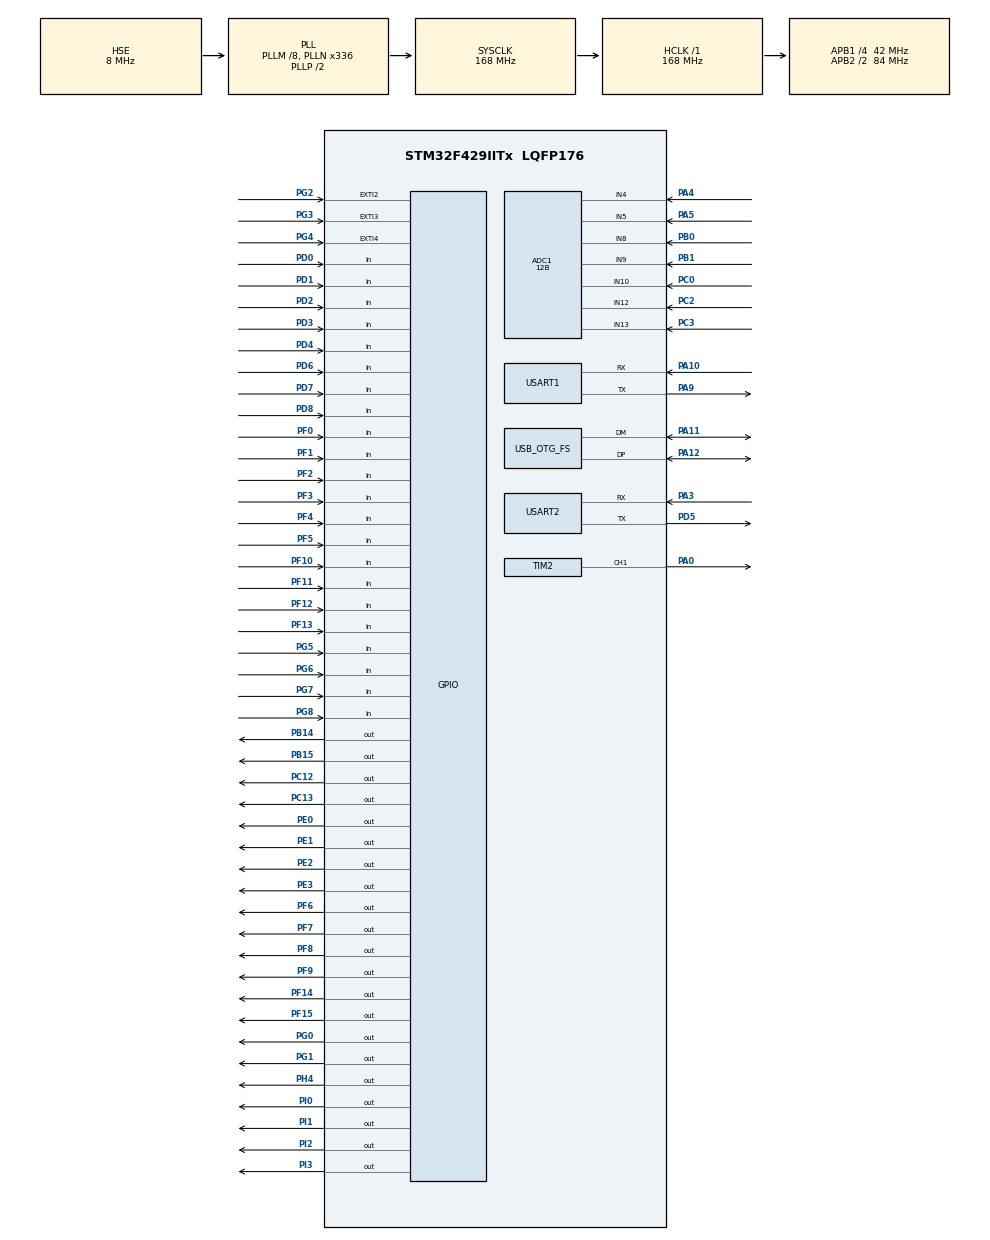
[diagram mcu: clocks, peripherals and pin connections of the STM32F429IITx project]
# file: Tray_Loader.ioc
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ADC1.Channel-0\#ChannelRegularConversion=ADC_CHANNEL_5
ADC1.Channel-1\#ChannelRegularConversion=ADC_CHANNEL_4
ADC1.ClockPrescaler=ADC_CLOCK_SYNC_PCLK_DIV4
ADC1.ContinuousConvMode=DISABLE
ADC1.DMAContinuousRequests=DISABLE
ADC1.DataAlign=ADC_DATAALIGN_RIGHT
ADC1.DiscontinuousConvMode=DISABLE
ADC1.EOCSelection=ADC_EOC_SINGLE_CONV
ADC1.EnableAnalogWatchDog=false
ADC1.ExternalTrigConv=ADC_SOFTWARE_START
ADC1.ExternalTrigConvEdge=ADC_EXTERNALTRIGCONVEDGE_NONE
ADC1.InjNumberOfConversion=0
ADC1.NbrOfConversion=2
ADC1.NbrOfConversionFlag=1
ADC1.Rank-0\#ChannelRegularConversion=1
ADC1.Rank-1\#ChannelRegularConversion=2
ADC1.Resolution=ADC_RESOLUTION_12B
ADC1.SamplingTime-0\#ChannelRegularConversion=ADC_SAMPLETIME_3CYCLES
ADC1.SamplingTime-1\#ChannelRegularConversion=ADC_SAMPLETIME_3CYCLES
ADC1.ScanConvMode=ENABLE
ADC1.master=1
Dma.Request0=USART1_RX
Dma.USART1_RX.0.Direction=DMA_PERIPH_TO_MEMORY
Dma.USART1_RX.0.FIFOMode=DMA_FIFOMODE_DISABLE
Dma.USART1_RX.0.Instance=DMA2_Stream2
Dma.USART1_RX.0.MemDataAlignment=DMA_MDATAALIGN_BYTE
Dma.USART1_RX.0.MemInc=DMA_MINC_ENABLE
Dma.USART1_RX.0.Mode=DMA_NORMAL
Dma.USART1_RX.0.PeriphDataAlignment=DMA_PDATAALIGN_BYTE
Dma.USART1_RX.0.PeriphInc=DMA_PINC_DISABLE
Dma.USART1_RX.0.Priority=DMA_PRIORITY_LOW
Mcu.Family=STM32F4
Mcu.Name=STM32F429IITx
Mcu.Package=LQFP176
NVIC.DMA2_Stream2_IRQn=true\:0\:0\:false\:false\:true\:false
NVIC.EXTI2_IRQn=true\:1\:0\:true\:false\:true\:true
NVIC.EXTI3_IRQn=true\:3\:0\:true\:false\:true\:true
NVIC.EXTI4_IRQn=true\:4\:0\:true\:false\:true\:true
NVIC.OTG_FS_IRQn=true\:0\:0\:false\:false\:true\:false
NVIC.PriorityGroup=NVIC_PRIORITYGROUP_4
NVIC.TIM2_IRQn=true\:1\:0\:true\:false\:true\:true
PA0/WKUP.Signal=S_TIM2_CH1_ETR
PA10.Mode=Asynchronous
PA10.Signal=USART1_RX
PA11.Mode=Host_Only
PA11.Signal=USB_OTG_FS_DM
PA12.Mode=Host_Only
PA12.Signal=USB_OTG_FS_DP
PA3.Mode=Asynchronous
PA3.Signal=USART2_RX
PA4.Signal=ADCx_IN4
PA5.Signal=ADCx_IN5
PA9.Mode=Asynchronous
PA9.Signal=USART1_TX
PB0.Signal=ADCx_IN8
PB1.Signal=ADCx_IN9
PB14.Signal=GPIO_Output
PB15.Signal=GPIO_Output
PC0.Signal=ADCx_IN10
PC12.Signal=GPIO_Output
PC13.Signal=GPIO_Output
PC14/OSC32_IN.Mode=LSE-External-Oscillator
PC14/OSC32_IN.Signal=RCC_OSC32_IN
PC15/OSC32_OUT.Mode=LSE-External-Oscillator
PC15/OSC32_OUT.Signal=RCC_OSC32_OUT
PC2.Signal=ADCx_IN12
PC3.Signal=ADCx_IN13
PD0.Signal=GPIO_Input
PD1.Signal=GPIO_Input
PD2.Signal=GPIO_Input
PD3.Signal=GPIO_Input
PD4.Signal=GPIO_Input
PD5.Mode=Asynchronous
PD5.Signal=USART2_TX
PD6.Signal=GPIO_Input
PD7.Signal=GPIO_Input
PD8.Signal=GPIO_Input
PE0.Signal=GPIO_Output
PE1.Signal=GPIO_Output
PE2.Signal=GPIO_Output
PE3.Signal=GPIO_Output
PF0.Signal=GPIO_Input
PF1.Signal=GPIO_Input
PF10.Signal=GPIO_Input
PF11.Signal=GPIO_Input
PF12.Signal=GPIO_Input
PF13.Signal=GPIO_Input
PF14.Signal=GPIO_Output
PF15.Signal=GPIO_Output
PF2.Signal=GPIO_Input
PF3.Signal=GPIO_Input
PF4.Signal=GPIO_Input
PF5.Signal=GPIO_Input
PF6.Signal=GPIO_Output
PF7.Signal=GPIO_Output
PF8.Signal=GPIO_Output
PF9.Signal=GPIO_Output
PG0.Signal=GPIO_Output
PG1.Signal=GPIO_Output
PG2.GPIO_ModeDefaultEXTI=GPIO_MODE_IT_FALLING
PG2.Signal=GPXTI2
PG3.GPIO_ModeDefaultEXTI=GPIO_MODE_IT_FALLING
PG3.Signal=GPXTI3
PG4.GPIO_ModeDefaultEXTI=GPIO_MODE_IT_FALLING
PG4.Signal=GPXTI4
PG5.Signal=GPIO_Input
PG6.Signal=GPIO_Input
PG7.Signal=GPIO_Input
PG8.Signal=GPIO_Input
PH0/OSC_IN.Mode=HSE-External-Oscillator
PH0/OSC_IN.Signal=RCC_OSC_IN
PH1/OSC_OUT.Mode=HSE-External-Oscillator
PH1/OSC_OUT.Signal=RCC_OSC_OUT
PH4.Signal=GPIO_Output
PI0.Signal=GPIO_Output
PI1.Signal=GPIO_Output
PI2.Signal=GPIO_Output
PI3.Signal=GPIO_Output
ProjectManager.HeapSize=0x4000
ProjectManager.StackSize=0x4000
ProjectManager.TargetToolchain=MDK-ARM V5
RCC.48MHZClocksFreq_Value=48000000
RCC.AHBFreq_Value=168000000
RCC.APB1CLKDivider=RCC_HCLK_DIV4
RCC.APB1Freq_Value=42000000
RCC.APB1TimFreq_Value=84000000
RCC.APB2CLKDivider=RCC_HCLK_DIV2
RCC.APB2Freq_Value=84000000
RCC.APB2TimFreq_Value=168000000
RCC.CortexFreq_Value=168000000
RCC.HCLKFreq_Value=168000000
RCC.HSE_VALUE=8000000
RCC.HSI_VALUE=16000000
RCC.PLLM=8
RCC.PLLN=336
RCC.PLLQ=7
RCC.RCC_RTC_Clock_Source=RCC_RTCCLKSOURCE_LSE
RCC.RCC_RTC_Clock_SourceVirtual=RCC_RTCCLKSOURCE_LSE
RCC.SYSCLKFreq_VALUE=168000000
RCC.SYSCLKSource=RCC_SYSCLKSOURCE_PLLCLK
RCC.VCOOutputFreq_Value=336000000
SH.ADCx_IN10.0=ADC1_IN10,IN10
SH.ADCx_IN12.0=ADC1_IN12,IN12
SH.ADCx_IN13.0=ADC1_IN13,IN13
SH.ADCx_IN4.0=ADC1_IN4,IN4
SH.ADCx_IN5.0=ADC1_IN5,IN5
SH.ADCx_IN8.0=ADC1_IN8,IN8
SH.ADCx_IN9.0=ADC1_IN9,IN9
SH.S_TIM2_CH1_ETR.0=TIM2_CH1,PWM Generation1 CH1
TIM1.Period=65535-1
TIM1.Prescaler=168-1
TIM2.Channel-PWM\ Generation1\ CH1=TIM_CHANNEL_1
TIM2.Period=1000-1
TIM2.Prescaler=8400-1
USART1.VirtualMode=VM_ASYNC
USART2.VirtualMode=VM_ASYNC
USB_HOST.USBH_HandleTypeDef-MSC_FS=hUsbHostFS
USB_HOST.VirtualModeFS=Msc
USB_OTG_FS.VirtualMode=Host_Only
USB_OTG_FS.phy_itface=HCD_PHY_EMBEDDED
VP_CRC_VS_CRC.Mode=CRC_Activate
VP_FATFS_VS_USB.Mode=USB
VP_RTC_VS_RTC_Activate.Mode=RTC_Enabled
VP_TIM1_VS_ClockSourceINT.Mode=Internal
VP_TIM2_VS_ClockSourceINT.Mode=Internal
VP_USB_HOST_VS_USB_HOST_MSC_FS.Mode=MSC_FS
board=custom

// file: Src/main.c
/**
  ******************************************************************************
  * @file           : main.c
  * @brief          : Main program body
  ******************************************************************************
  * This notice applies to any and all portions of this file
  * that are not between comment pairs USER CODE BEGIN and
  * USER CODE END. Other portions of this file, whether
  * inserted by the user or by software development tools
  * are owned by their respective copyright owners.
  *
  * Copyright (c) 2021 STMicroelectronics International N.V.
  * All rights reserved.
  *
  * Redistribution and use in source and binary forms, with or without
  * modification, are permitted, provided that the following conditions are met:
  *
  * 1. Redistribution of source code must retain the above copyright notice,
  *    this list of conditions and the following disclaimer.
  * 2. Redistributions in binary form must reproduce the above copyright notice,
  *    this list of conditions and the following disclaimer in the documentation
  *    and/or other materials provided with the distribution.
  * 3. Neither the name of STMicroelectronics nor the names of other
  *    contributors to this software may be used to endorse or promote products
  *    derived from this software without specific written permission.
  * 4. This software, including modifications and/or derivative works of this
  *    software, must execute solely and exclusively on microcontroller or
  *    microprocessor devices manufactured by or for STMicroelectronics.
  * 5. Redistribution and use of this software other than as permitted under
  *    this license is void and will automatically terminate your rights under
  *    this license.
  *
  * THIS SOFTWARE IS PROVIDED BY STMICROELECTRONICS AND CONTRIBUTORS "AS IS"
  * AND ANY EXPRESS, IMPLIED OR STATUTORY WARRANTIES, INCLUDING, BUT NOT
  * LIMITED TO, THE IMPLIED WARRANTIES OF MERCHANTABILITY, FITNESS FOR A
  * PARTICULAR PURPOSE AND NON-INFRINGEMENT OF THIRD PARTY INTELLECTUAL PROPERTY
  * RIGHTS ARE DISCLAIMED TO THE FULLEST EXTENT PERMITTED BY LAW. IN NO EVENT
  * SHALL STMICROELECTRONICS OR CONTRIBUTORS BE LIABLE FOR ANY DIRECT, INDIRECT,
  * INCIDENTAL, SPECIAL, EXEMPLARY, OR CONSEQUENTIAL DAMAGES (INCLUDING, BUT NOT
  * LIMITED TO, PROCUREMENT OF SUBSTITUTE GOODS OR SERVICES; LOSS OF USE, DATA,
  * OR PROFITS; OR BUSINESS INTERRUPTION) HOWEVER CAUSED AND ON ANY THEORY OF
  * LIABILITY, WHETHER IN CONTRACT, STRICT LIABILITY, OR TORT (INCLUDING
  * NEGLIGENCE OR OTHERWISE) ARISING IN ANY WAY OUT OF THE USE OF THIS SOFTWARE,
  * EVEN IF ADVISED OF THE POSSIBILITY OF SUCH DAMAGE.
  *
  ******************************************************************************
  */
#include "main.h"
#include "stm32f4xx_hal.h"
#include "fatfs.h"
#include "usb_host.h"
#include "Task_Main.h"

ADC_HandleTypeDef hadc1;

CRC_HandleTypeDef hcrc;

RTC_HandleTypeDef hrtc;

TIM_HandleTypeDef htim1;
TIM_HandleTypeDef htim2;

UART_HandleTypeDef huart1;
UART_HandleTypeDef huart2;
DMA_HandleTypeDef hdma_usart1_rx;

extern uint8_t rxBuffer[MAX_SIZE];

void SystemClock_Config(void);
static void MX_GPIO_Init(void);
static void MX_DMA_Init(void);
static void MX_ADC1_Init(void);
static void MX_CRC_Init(void);
static void MX_RTC_Init(void);
static void MX_TIM2_Init(void);
static void MX_USART1_UART_Init(void);
static void MX_USART2_UART_Init(void);
static void MX_TIM1_Init(void);
void MX_USB_HOST_Process(void);

void HAL_TIM_MspPostInit(TIM_HandleTypeDef *htim);

int main(void)
{
    HAL_Init();

    SystemClock_Config();

    MX_GPIO_Init();
    MX_DMA_Init();
    MX_ADC1_Init();
    MX_CRC_Init();
    MX_RTC_Init();
    MX_TIM2_Init();
    MX_USART1_UART_Init();
    MX_USART2_UART_Init();
    MX_FATFS_Init();
    MX_USB_HOST_Init();
    MX_TIM1_Init();

    HAL_TIM_Base_Start(&htim1);
    __HAL_TIM_ENABLE_IT(&htim2, TIM_IT_UPDATE);

    HAL_UART_Receive_DMA (&huart1, rxBuffer, RX_LEN);
    while (1)
    {
        Task_Main();
    }
}

void SystemClock_Config(void)
{

  RCC_OscInitTypeDef RCC_OscInitStruct;
  RCC_ClkInitTypeDef RCC_ClkInitStruct;
  RCC_PeriphCLKInitTypeDef PeriphClkInitStruct;

    /**Configure the main internal regulator output voltage
    */
  __HAL_RCC_PWR_CLK_ENABLE();

  __HAL_PWR_VOLTAGESCALING_CONFIG(PWR_REGULATOR_VOLTAGE_SCALE1);

    /**Initializes the CPU, AHB and APB busses clocks
    */
  RCC_OscInitStruct.OscillatorType = RCC_OSCILLATORTYPE_HSE|RCC_OSCILLATORTYPE_LSE;
  RCC_OscInitStruct.HSEState = RCC_HSE_ON;
  RCC_OscInitStruct.LSEState = RCC_LSE_ON;
  RCC_OscInitStruct.PLL.PLLState = RCC_PLL_ON;
  RCC_OscInitStruct.PLL.PLLSource = RCC_PLLSOURCE_HSE;
  RCC_OscInitStruct.PLL.PLLM = 8;
  RCC_OscInitStruct.PLL.PLLN = 336;
  RCC_OscInitStruct.PLL.PLLP = RCC_PLLP_DIV2;
  RCC_OscInitStruct.PLL.PLLQ = 7;
  if (HAL_RCC_OscConfig(&RCC_OscInitStruct) != HAL_OK)
  {
    _Error_Handler(__FILE__, __LINE__);
  }

    /**Initializes the CPU, AHB and APB busses clocks
    */
  RCC_ClkInitStruct.ClockType = RCC_CLOCKTYPE_HCLK|RCC_CLOCKTYPE_SYSCLK
                              |RCC_CLOCKTYPE_PCLK1|RCC_CLOCKTYPE_PCLK2;
  RCC_ClkInitStruct.SYSCLKSource = RCC_SYSCLKSOURCE_PLLCLK;
  RCC_ClkInitStruct.AHBCLKDivider = RCC_SYSCLK_DIV1;
  RCC_ClkInitStruct.APB1CLKDivider = RCC_HCLK_DIV4;
  RCC_ClkInitStruct.APB2CLKDivider = RCC_HCLK_DIV2;

  if (HAL_RCC_ClockConfig(&RCC_ClkInitStruct, FLASH_LATENCY_5) != HAL_OK)
  {
    _Error_Handler(__FILE__, __LINE__);
  }

  PeriphClkInitStruct.PeriphClockSelection = RCC_PERIPHCLK_RTC;
  PeriphClkInitStruct.RTCClockSelection = RCC_RTCCLKSOURCE_LSE;
  if (HAL_RCCEx_PeriphCLKConfig(&PeriphClkInitStruct) != HAL_OK)
  {
    _Error_Handler(__FILE__, __LINE__);
  }

    /**Configure the Systick interrupt time
    */
  HAL_SYSTICK_Config(HAL_RCC_GetHCLKFreq()/1000);

    /**Configure the Systick
    */
  HAL_SYSTICK_CLKSourceConfig(SYSTICK_CLKSOURCE_HCLK);

  /* SysTick_IRQn interrupt configuration */
  HAL_NVIC_SetPriority(SysTick_IRQn, 0, 0);
}

/* ADC1 init function */
static void MX_ADC1_Init(void)
{

  ADC_ChannelConfTypeDef sConfig;

    /**Configure the global features of the ADC (Clock, Resolution, Data Alignment and number of conversion)
    */
  hadc1.Instance = ADC1;
  hadc1.Init.ClockPrescaler = ADC_CLOCK_SYNC_PCLK_DIV4;
  hadc1.Init.Resolution = ADC_RESOLUTION_12B;
  hadc1.Init.ScanConvMode = ENABLE;
  hadc1.Init.ContinuousConvMode = DISABLE;
  hadc1.Init.DiscontinuousConvMode = DISABLE;
  hadc1.Init.ExternalTrigConvEdge = ADC_EXTERNALTRIGCONVEDGE_NONE;
  hadc1.Init.ExternalTrigConv = ADC_SOFTWARE_START;
  hadc1.Init.DataAlign = ADC_DATAALIGN_RIGHT;
  hadc1.Init.NbrOfConversion = 1;
  hadc1.Init.DMAContinuousRequests = DISABLE;
  hadc1.Init.EOCSelection = ADC_EOC_SINGLE_CONV;
  if (HAL_ADC_Init(&hadc1) != HAL_OK)
  {
    _Error_Handler(__FILE__, __LINE__);
  }

  /*
    //Configure for the selected ADC regular channel its corresponding rank in the sequencer and its sample time.
  sConfig.Channel = ADC_CHANNEL_5;
  sConfig.Rank = 1;
  sConfig.SamplingTime = ADC_SAMPLETIME_3CYCLES;
  if (HAL_ADC_ConfigChannel(&hadc1, &sConfig) != HAL_OK)
  {
    _Error_Handler(__FILE__, __LINE__);
  }
  */

    //Configure for the selected ADC regular channel its corresponding rank in the sequencer and its sample time.
  sConfig.Channel = ADC_CHANNEL_5;
  sConfig.Rank = 1;
  if (HAL_ADC_ConfigChannel(&hadc1, &sConfig) != HAL_OK)
  {
    _Error_Handler(__FILE__, __LINE__);
  }
}

/* CRC init function */
static void MX_CRC_Init(void)
{

  hcrc.Instance = CRC;
  if (HAL_CRC_Init(&hcrc) != HAL_OK)
  {
    _Error_Handler(__FILE__, __LINE__);
  }

}

/* RTC init function */
static void MX_RTC_Init(void)
{

    /**Initialize RTC Only
    */
  hrtc.Instance = RTC;
  hrtc.Init.HourFormat = RTC_HOURFORMAT_24;
  hrtc.Init.AsynchPrediv = 127;
  hrtc.Init.SynchPrediv = 255;
  hrtc.Init.OutPut = RTC_OUTPUT_DISABLE;
  hrtc.Init.OutPutPolarity = RTC_OUTPUT_POLARITY_HIGH;
  hrtc.Init.OutPutType = RTC_OUTPUT_TYPE_OPENDRAIN;
  if (HAL_RTC_Init(&hrtc) != HAL_OK)
  {
    _Error_Handler(__FILE__, __LINE__);
  }

}

/* TIM1 init function */
static void MX_TIM1_Init(void)
{

  TIM_ClockConfigTypeDef sClockSourceConfig;
  TIM_MasterConfigTypeDef sMasterConfig;

  htim1.Instance = TIM1;
  htim1.Init.Prescaler = 168-1;
  htim1.Init.CounterMode = TIM_COUNTERMODE_UP;
  htim1.Init.Period = 65535-1;
  htim1.Init.ClockDivision = TIM_CLOCKDIVISION_DIV1;
  htim1.Init.RepetitionCounter = 0;
  if (HAL_TIM_Base_Init(&htim1) != HAL_OK)
  {
    _Error_Handler(__FILE__, __LINE__);
  }

  sClockSourceConfig.ClockSource = TIM_CLOCKSOURCE_INTERNAL;
  if (HAL_TIM_ConfigClockSource(&htim1, &sClockSourceConfig) != HAL_OK)
  {
    _Error_Handler(__FILE__, __LINE__);
  }

  sMasterConfig.MasterOutputTrigger = TIM_TRGO_RESET;
  sMasterConfig.MasterSlaveMode = TIM_MASTERSLAVEMODE_DISABLE;
  if (HAL_TIMEx_MasterConfigSynchronization(&htim1, &sMasterConfig) != HAL_OK)
  {
    _Error_Handler(__FILE__, __LINE__);
  }

}

/* TIM2 init function */
static void MX_TIM2_Init(void)
{

    //TIME UPDATE FREQUENCY = TIM_CLK/(TIM_PSC+1)/(PERIOD + 1)
    // PWM FREQUENCY = 20 KHz
  TIM_ClockConfigTypeDef sClockSourceConfig;
  TIM_MasterConfigTypeDef sMasterConfig;
  TIM_OC_InitTypeDef sConfigOC;

  htim2.Instance = TIM2;
  htim2.Init.Prescaler = 42-1;     //8400-1;
  htim2.Init.CounterMode = TIM_COUNTERMODE_UP;
  htim2.Init.Period = 100-1;        // 1000-1
  htim2.Init.ClockDivision = TIM_CLOCKDIVISION_DIV1;
  if (HAL_TIM_Base_Init(&htim2) != HAL_OK)
  {
    _Error_Handler(__FILE__, __LINE__);
  }

  sClockSourceConfig.ClockSource = TIM_CLOCKSOURCE_INTERNAL;
  if (HAL_TIM_ConfigClockSource(&htim2, &sClockSourceConfig) != HAL_OK)
  {
    _Error_Handler(__FILE__, __LINE__);
  }

  if (HAL_TIM_PWM_Init(&htim2) != HAL_OK)
  {
    _Error_Handler(__FILE__, __LINE__);
  }

  sMasterConfig.MasterOutputTrigger = TIM_TRGO_RESET;
  sMasterConfig.MasterSlaveMode = TIM_MASTERSLAVEMODE_DISABLE;
  if (HAL_TIMEx_MasterConfigSynchronization(&htim2, &sMasterConfig) != HAL_OK)
  {
    _Error_Handler(__FILE__, __LINE__);
  }

  sConfigOC.OCMode = TIM_OCMODE_PWM1;
  sConfigOC.Pulse = 25;
  sConfigOC.OCPolarity = TIM_OCPOLARITY_HIGH;
  sConfigOC.OCFastMode = TIM_OCFAST_DISABLE;
  if (HAL_TIM_PWM_ConfigChannel(&htim2, &sConfigOC, TIM_CHANNEL_1) != HAL_OK)
  {
    _Error_Handler(__FILE__, __LINE__);
  }

  HAL_TIM_MspPostInit(&htim2);

}

/* USART1 init function */
static void MX_USART1_UART_Init(void)
{

  huart1.Instance = USART1;
  huart1.Init.BaudRate = 115200;
  huart1.Init.WordLength = UART_WORDLENGTH_8B;
  huart1.Init.StopBits = UART_STOPBITS_1;
  huart1.Init.Parity = UART_PARITY_NONE;
  huart1.Init.Mode = UART_MODE_TX_RX;
  huart1.Init.HwFlowCtl = UART_HWCONTROL_NONE;
  huart1.Init.OverSampling = UART_OVERSAMPLING_16;
  if (HAL_UART_Init(&huart1) != HAL_OK)
  {
    _Error_Handler(__FILE__, __LINE__);
  }

}

/* USART2 init function */
static void MX_USART2_UART_Init(void)
{

  huart2.Instance = USART2;
  huart2.Init.BaudRate = 115200;
  huart2.Init.WordLength = UART_WORDLENGTH_8B;
  huart2.Init.StopBits = UART_STOPBITS_1;
  huart2.Init.Parity = UART_PARITY_NONE;
  huart2.Init.Mode = UART_MODE_TX_RX;
  huart2.Init.HwFlowCtl = UART_HWCONTROL_NONE;
  huart2.Init.OverSampling = UART_OVERSAMPLING_16;
  if (HAL_UART_Init(&huart2) != HAL_OK)
  {
    _Error_Handler(__FILE__, __LINE__);
  }

}

static void MX_DMA_Init(void)
{
  /* DMA controller clock enable */
  __HAL_RCC_DMA2_CLK_ENABLE();

  /* DMA interrupt init */
  /* DMA2_Stream2_IRQn interrupt configuration */
  HAL_NVIC_SetPriority(DMA2_Stream2_IRQn, 0, 0);
  HAL_NVIC_EnableIRQ(DMA2_Stream2_IRQn);

}

/** Configure pins as
        * Analog
        * Input
        * Output
        * EVENT_OUT
        * EXTI
*/
static void MX_GPIO_Init(void)
{

  GPIO_InitTypeDef GPIO_InitStruct;

  /* GPIO Ports Clock Enable */
  __HAL_RCC_GPIOE_CLK_ENABLE();
  __HAL_RCC_GPIOC_CLK_ENABLE();
  __HAL_RCC_GPIOF_CLK_ENABLE();
  __HAL_RCC_GPIOH_CLK_ENABLE();
  __HAL_RCC_GPIOA_CLK_ENABLE();
  __HAL_RCC_GPIOB_CLK_ENABLE();
  __HAL_RCC_GPIOG_CLK_ENABLE();
  __HAL_RCC_GPIOD_CLK_ENABLE();
  __HAL_RCC_GPIOI_CLK_ENABLE();

  /*Configure GPIO pin Output Level */
  HAL_GPIO_WritePin(GPIOE, GPIO_PIN_2|GPIO_PIN_3|GPIO_PIN_0|GPIO_PIN_1, GPIO_PIN_RESET);

  /*Configure GPIO pin Output Level */
  HAL_GPIO_WritePin(GPIOC, GPIO_PIN_13|GPIO_PIN_12, GPIO_PIN_RESET);

  /*Configure GPIO pin Output Level */
  HAL_GPIO_WritePin(GPIOF, GPIO_PIN_6|GPIO_PIN_7|GPIO_PIN_8|GPIO_PIN_9
                          |GPIO_PIN_14|GPIO_PIN_15, GPIO_PIN_RESET);

  /*Configure GPIO pin Output Level */
  HAL_GPIO_WritePin(GPIOH, GPIO_PIN_4, GPIO_PIN_RESET);

  /*Configure GPIO pin Output Level */
  HAL_GPIO_WritePin(GPIOG, GPIO_PIN_0|GPIO_PIN_1, GPIO_PIN_RESET);

  /*Configure GPIO pin Output Level */
  HAL_GPIO_WritePin(GPIOB, GPIO_PIN_14|GPIO_PIN_15, GPIO_PIN_RESET);

  /*Configure GPIO pin Output Level */
  HAL_GPIO_WritePin(GPIOI, GPIO_PIN_0|GPIO_PIN_1|GPIO_PIN_2|GPIO_PIN_3, GPIO_PIN_RESET);

  /*Configure GPIO pins : PE2 PE3 PE0 PE1 */
  GPIO_InitStruct.Pin = GPIO_PIN_2|GPIO_PIN_3|GPIO_PIN_0|GPIO_PIN_1;
  GPIO_InitStruct.Mode = GPIO_MODE_OUTPUT_PP;
  GPIO_InitStruct.Pull = GPIO_NOPULL;
  GPIO_InitStruct.Speed = GPIO_SPEED_FREQ_LOW;
  HAL_GPIO_Init(GPIOE, &GPIO_InitStruct);

  /*Configure GPIO pins : PC13 PC12 */
  GPIO_InitStruct.Pin = GPIO_PIN_13|GPIO_PIN_12;
  GPIO_InitStruct.Mode = GPIO_MODE_OUTPUT_PP;
  GPIO_InitStruct.Pull = GPIO_NOPULL;
  GPIO_InitStruct.Speed = GPIO_SPEED_FREQ_LOW;
  HAL_GPIO_Init(GPIOC, &GPIO_InitStruct);

  /*Configure GPIO pins : PF0 PF1 PF2 PF3
                           PF4 PF5 PF10 PF11
                           PF12 PF13 */
  GPIO_InitStruct.Pin = GPIO_PIN_0|GPIO_PIN_1|GPIO_PIN_2|GPIO_PIN_3
                          |GPIO_PIN_4|GPIO_PIN_5|GPIO_PIN_10|GPIO_PIN_11
                          |GPIO_PIN_12|GPIO_PIN_13;
  GPIO_InitStruct.Mode = GPIO_MODE_INPUT;
  GPIO_InitStruct.Pull = GPIO_NOPULL;
  HAL_GPIO_Init(GPIOF, &GPIO_InitStruct);

  /*Configure GPIO pins : PF6 PF7 PF8 PF9
                           PF14 PF15 */
  GPIO_InitStruct.Pin = GPIO_PIN_6|GPIO_PIN_7|GPIO_PIN_8|GPIO_PIN_9
                          |GPIO_PIN_14|GPIO_PIN_15;
  GPIO_InitStruct.Mode = GPIO_MODE_OUTPUT_PP;
  GPIO_InitStruct.Pull = GPIO_NOPULL;
  GPIO_InitStruct.Speed = GPIO_SPEED_FREQ_LOW;
  HAL_GPIO_Init(GPIOF, &GPIO_InitStruct);

  /*Configure GPIO pin : PH4 */
  GPIO_InitStruct.Pin = GPIO_PIN_4;
  GPIO_InitStruct.Mode = GPIO_MODE_OUTPUT_PP;
  GPIO_InitStruct.Pull = GPIO_NOPULL;
  GPIO_InitStruct.Speed = GPIO_SPEED_FREQ_LOW;
  HAL_GPIO_Init(GPIOH, &GPIO_InitStruct);

  /*Configure GPIO pins : PG0 PG1 */
  GPIO_InitStruct.Pin = GPIO_PIN_0|GPIO_PIN_1;
  GPIO_InitStruct.Mode = GPIO_MODE_OUTPUT_PP;
  GPIO_InitStruct.Pull = GPIO_NOPULL;
  GPIO_InitStruct.Speed = GPIO_SPEED_FREQ_LOW;
  HAL_GPIO_Init(GPIOG, &GPIO_InitStruct);

  /*Configure GPIO pins : PB14 PB15 */
  GPIO_InitStruct.Pin = GPIO_PIN_14|GPIO_PIN_15;
  GPIO_InitStruct.Mode = GPIO_MODE_OUTPUT_PP;
  GPIO_InitStruct.Pull = GPIO_NOPULL;
  GPIO_InitStruct.Speed = GPIO_SPEED_FREQ_LOW;
  HAL_GPIO_Init(GPIOB, &GPIO_InitStruct);

  /*Configure GPIO pins : PD8 PD0 PD1 PD2
                           PD3 PD4 PD6 PD7 */
  GPIO_InitStruct.Pin = GPIO_PIN_0|GPIO_PIN_1|GPIO_PIN_2|GPIO_PIN_3;
  GPIO_InitStruct.Mode = GPIO_MODE_INPUT;
  GPIO_InitStruct.Pull = GPIO_NOPULL;
  HAL_GPIO_Init(GPIOD, &GPIO_InitStruct);

  GPIO_InitStruct.Pin = GPIO_PIN_4|GPIO_PIN_6|GPIO_PIN_7|GPIO_PIN_8;
  GPIO_InitStruct.Mode = GPIO_MODE_INPUT;
  GPIO_InitStruct.Pull = GPIO_PULLUP;
  HAL_GPIO_Init(GPIOD, &GPIO_InitStruct);

  /*Configure GPIO pins : PG2 PG3 PG4 */
  /* PG2 falling input interrupt  */
  GPIO_InitStruct.Pin = GPIO_PIN_2; //|GPIO_PIN_3|GPIO_PIN_4;
  GPIO_InitStruct.Mode = GPIO_MODE_IT_FALLING;
  GPIO_InitStruct.Pull = GPIO_NOPULL;
  HAL_GPIO_Init(GPIOG, &GPIO_InitStruct);
  /* PG3, PG4 input */
  GPIO_InitStruct.Pin = GPIO_PIN_3|GPIO_PIN_4;
  GPIO_InitStruct.Mode = GPIO_MODE_INPUT;
  GPIO_InitStruct.Pull = GPIO_PULLUP;
  HAL_GPIO_Init(GPIOG, &GPIO_InitStruct);

  /*Configure GPIO pins : PG5 PG6 PG7 PG8 */
  GPIO_InitStruct.Pin = GPIO_PIN_5|GPIO_PIN_6|GPIO_PIN_7|GPIO_PIN_8;
  GPIO_InitStruct.Mode = GPIO_MODE_INPUT;
  GPIO_InitStruct.Pull = GPIO_NOPULL;
  HAL_GPIO_Init(GPIOG, &GPIO_InitStruct);

  /*Configure GPIO pins : PI0 PI1 PI2 PI3 */
  GPIO_InitStruct.Pin = GPIO_PIN_0|GPIO_PIN_1|GPIO_PIN_2|GPIO_PIN_3;
  GPIO_InitStruct.Mode = GPIO_MODE_OUTPUT_PP;
  GPIO_InitStruct.Pull = GPIO_NOPULL;
  GPIO_InitStruct.Speed = GPIO_SPEED_FREQ_LOW;
  HAL_GPIO_Init(GPIOI, &GPIO_InitStruct);

  GPIO_InitStruct.Pin = GPIO_PIN_4|GPIO_PIN_6|GPIO_PIN_7|GPIO_PIN_5;
  GPIO_InitStruct.Mode = GPIO_MODE_INPUT;
  GPIO_InitStruct.Pull = GPIO_PULLUP;
  HAL_GPIO_Init(GPIOI, &GPIO_InitStruct);

  /* EXTI interrupt init */
  HAL_NVIC_SetPriority(EXTI2_IRQn, 1, 0);
  HAL_NVIC_EnableIRQ(EXTI2_IRQn);

  /*
  HAL_NVIC_SetPriority(EXTI3_IRQn, 3, 0);
  HAL_NVIC_EnableIRQ(EXTI3_IRQn);

  HAL_NVIC_SetPriority(EXTI4_IRQn, 4, 0);
  HAL_NVIC_EnableIRQ(EXTI4_IRQn);
  */

}

void _Error_Handler(char *file, int line)
{
  while(1)
  {
  }
}

/************************ (C) COPYRIGHT STMicroelectronics *****END OF FILE****/
